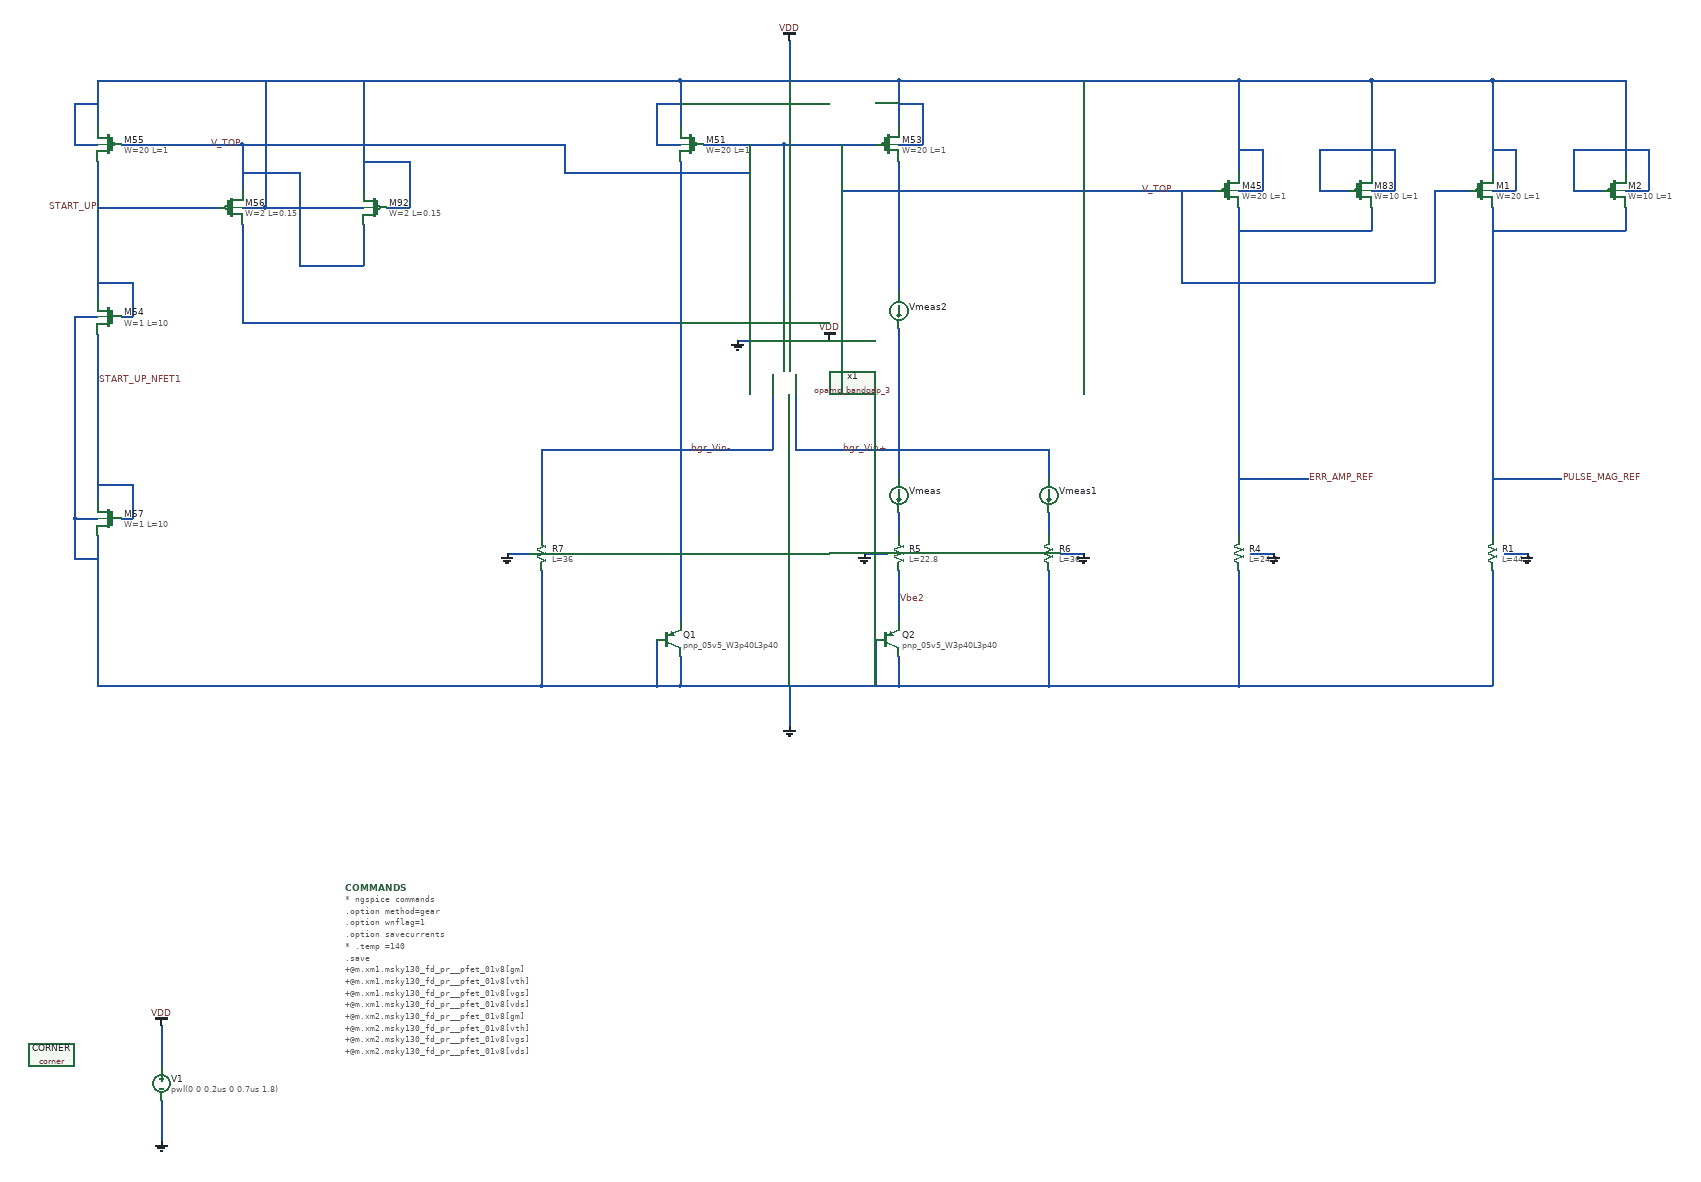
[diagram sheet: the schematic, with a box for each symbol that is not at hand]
v {xschem version=3.4.6 file_version=1.2}
G {}
K {}
V {}
S {}
E {}
B 2 1440 -1170 2430 -300 {flags=graph
y1=-0.0094
y2=1.3
ypos1=0
ypos2=2
divy=5
subdivy=1
unity=1
x1=0
x2=1e-06
divx=5
subdivx=1
xlabmag=1.0
ylabmag=1.0
node=err_amp_ref
color=7
dataset=0
unitx=1
logx=0
logy=0
}
B 2 2630 -1170 3620 -300 {flags=graph
y1=-0.018
y2=1.7
ypos1=0
ypos2=2
divy=5
subdivy=1
unity=1
x1=0
x2=1e-06
divx=5
subdivx=1
xlabmag=1.0
ylabmag=1.0
node=pulse_mag_ref
color=7
dataset=0
unitx=1
logx=0
logy=0
}
B 2 3730 -1170 4720 -300 {flags=graph
y1=-1.4e-13
y2=0.75
ypos1=0
ypos2=2
divy=5
subdivy=1
unity=1
x1=0
x2=1e-06
divx=5
subdivx=1
xlabmag=1.0
ylabmag=1.0


dataset=0
unitx=1
logx=0
logy=0

color=6
node=v_top}
N 2480 -1740 2480 -1540 {lab=GND}
N 2480 -2590 2480 -2430 {
lab=VDD}
N 2480 -2400 2520 -2400 {lab=VDD}
N 2520 -2470 2520 -2400 {lab=VDD}
N 2480 -2470 2520 -2470 {lab=VDD}
N 2480 -2370 2480 -1800 {lab=ERR_AMP_REF}
N 2210 -2470 2210 -2400 {lab=V_TOP}
N 2210 -2590 2210 -2530 {lab=VDD}
N 2300 -2590 2480 -2590 {lab=VDD}
N 1510 -1540 1890 -1540 {
lab=GND}
N 1470 -1620 1470 -1540 {
lab=GND}
N 1850 -1620 1850 -1540 {
lab=GND}
N 1470 -1540 1510 -1540 {
lab=GND}
N 1550 -2480 1690 -2480 {
lab=V_TOP}
N 1690 -2480 1850 -2480 {
lab=V_TOP}
N 1510 -2590 1510 -2510 {
lab=VDD}
N 1510 -2590 1890 -2590 {
lab=VDD}
N 1890 -2590 1890 -2510 {
lab=VDD}
N 1890 -1740 1890 -1650 {lab=Vbe2}
N 2150 -1740 2150 -1540 {lab=GND}
N 1270 -1740 1270 -1540 {lab=GND}
N 1890 -2480 1930 -2480 {lab=VDD}
N 1930 -2550 1930 -2480 {lab=VDD}
N 1890 -2550 1930 -2550 {lab=VDD}
N 1470 -2480 1510 -2480 {lab=VDD}
N 1470 -2550 1470 -2480 {lab=VDD}
N 1470 -2550 1510 -2550 {lab=VDD}
N 1270 -1540 1470 -1540 {lab=GND}
N 1890 -1590 1890 -1540 {lab=GND}
N 1510 -1590 1510 -1540 {lab=GND}
N 750 -2480 750 -2400 {lab=V_TOP}
N 500 -2340 500 -2210 {lab=START_UP}
N 500 -2590 500 -2510 {
lab=VDD}
N 460 -2480 500 -2480 {lab=VDD}
N 460 -2550 460 -2480 {lab=VDD}
N 460 -2550 500 -2550 {lab=VDD}
N 500 -2450 500 -2340 {lab=START_UP}
N 500 -2590 1510 -2590 {lab=VDD}
N 750 -2480 1310 -2480 {lab=V_TOP}
N 1310 -2480 1310 -2430 {lab=V_TOP}
N 1310 -2430 1630 -2430 {lab=V_TOP}
N 500 -2370 710 -2370 {lab=START_UP}
N 500 -1540 1270 -1540 {lab=GND}
N 1630 -2480 1630 -2430 {lab=V_TOP}
N 750 -2170 1510 -2170 {lab=bgr_Vin-}
N 460 -2180 460 -2110 {lab=GND}
N 460 -2180 500 -2180 {lab=GND}
N 500 -1620 500 -1540 {lab=GND}
N 750 -2370 790 -2370 {lab=VDD}
N 500 -1800 500 -1620 {lab=GND}
N 540 -2480 750 -2480 {lab=V_TOP}
N 500 -2240 560 -2240 {lab=START_UP}
N 560 -2240 560 -2180 {lab=START_UP}
N 540 -2180 560 -2180 {lab=START_UP}
N 750 -2340 750 -2170 {lab=bgr_Vin-}
N 1270 -1950 1270 -1800 {lab=bgr_Vin-}
N 1700 -1540 1700 -1470 {lab=GND}
N 1210 -1770 1250 -1770 {lab=GND}
N 1830 -1770 1870 -1770 {lab=GND}
N 2170 -1770 2210 -1770 {lab=GND}
N 1610 -2140 1630 -2140 {lab=GND}
N 1750 -2140 1770 -2140 {lab=VDD}
N 790 -2590 790 -2370 {lab=VDD}
N 1710 -2080 1710 -1950 {lab=bgr_Vin+}
N 1670 -2080 1670 -1950 {lab=bgr_Vin-}
N 1710 -1950 2150 -1950 {lab=bgr_Vin+}
N 1270 -1950 1670 -1950 {lab=bgr_Vin-}
N 1690 -2480 1690 -2210 {lab=V_TOP}
N 1510 -1950 1510 -1650 {lab=bgr_Vin-}
N 1510 -2450 1510 -1950 {lab=bgr_Vin-}
N 460 -1760 500 -1760 {lab=GND}
N 460 -1830 460 -1760 {lab=GND}
N 460 -1830 500 -1830 {lab=GND}
N 500 -1890 560 -1890 {lab=START_UP_NFET1}
N 560 -1890 560 -1830 {lab=START_UP_NFET1}
N 540 -1830 560 -1830 {lab=START_UP_NFET1}
N 500 -2150 500 -1860 {lab=START_UP_NFET1}
N 1890 -1540 2150 -1540 {lab=GND}
N 2150 -1540 2480 -1540 {lab=GND}
N 1890 -2590 2300 -2590 {lab=VDD}
N 1790 -2400 2440 -2400 {lab=V_TOP}
N 1790 -2480 1790 -2400 {lab=V_TOP}
N 2500 -1770 2540 -1770 {lab=GND}
N 1700 -2660 1700 -2590 {lab=VDD}
N 460 -2110 460 -1830 {lab=GND}
N 2710 -2590 2710 -2430 {
lab=VDD}
N 2710 -2400 2750 -2400 {lab=VDD}
N 2750 -2470 2750 -2400 {lab=VDD}
N 2710 -2470 2750 -2470 {lab=VDD}
N 2620 -2400 2670 -2400 {lab=VDD}
N 2620 -2470 2620 -2400 {lab=VDD}
N 2620 -2470 2710 -2470 {lab=VDD}
N 2480 -2330 2710 -2330 {lab=ERR_AMP_REF}
N 2710 -2370 2710 -2330 {lab=ERR_AMP_REF}
N 960 -2340 960 -2270 {lab=V_TOP}
N 790 -2370 960 -2370 {lab=VDD}
N 960 -2590 960 -2400 {lab=VDD}
N 1000 -2370 1040 -2370 {lab=VDD}
N 1040 -2450 1040 -2370 {lab=VDD}
N 960 -2450 1040 -2450 {lab=VDD}
N 750 -2430 850 -2430 {lab=V_TOP}
N 850 -2430 850 -2270 {lab=V_TOP}
N 850 -2270 960 -2270 {lab=V_TOP}
N 2480 -1900 2600 -1900 {lab=ERR_AMP_REF}
N 610 -820 610 -750 {lab=GND}
N 610 -950 610 -880 {lab=VDD}
N 2480 -2590 2710 -2590 {lab=VDD}
N 2920 -1740 2920 -1540 {lab=GND}
N 2920 -2590 2920 -2430 {
lab=VDD}
N 2920 -2400 2960 -2400 {lab=VDD}
N 2960 -2470 2960 -2400 {lab=VDD}
N 2920 -2470 2960 -2470 {lab=VDD}
N 2920 -2370 2920 -1800 {lab=PULSE_MAG_REF}
N 2940 -1770 2980 -1770 {lab=GND}
N 3150 -2590 3150 -2430 {
lab=VDD}
N 3150 -2400 3190 -2400 {lab=VDD}
N 3190 -2470 3190 -2400 {lab=VDD}
N 3150 -2470 3190 -2470 {lab=VDD}
N 3060 -2400 3110 -2400 {lab=VDD}
N 3060 -2470 3060 -2400 {lab=VDD}
N 3060 -2470 3150 -2470 {lab=VDD}
N 2920 -2330 3150 -2330 {lab=PULSE_MAG_REF}
N 3150 -2370 3150 -2330 {lab=PULSE_MAG_REF}
N 2920 -1900 3040 -1900 {lab=PULSE_MAG_REF}
N 2920 -2590 3150 -2590 {lab=VDD}
N 2380 -2400 2380 -2240 {lab=V_TOP}
N 2380 -2240 2820 -2240 {lab=V_TOP}
N 2820 -2400 2820 -2240 {lab=V_TOP}
N 2820 -2400 2880 -2400 {lab=V_TOP}
N 2710 -2590 2920 -2590 {lab=VDD}
N 2480 -1540 2920 -1540 {lab=GND}
N 2150 -1840 2150 -1800 {lab=#net1}
N 2150 -1950 2150 -1900 {lab=bgr_Vin+}
N 1890 -1840 1890 -1800 {lab=#net2}
N 1890 -1950 1890 -1900 {lab=bgr_Vin+}
N 1890 -2160 1890 -1950 {lab=bgr_Vin+}
N 1890 -2450 1890 -2220 {lab=#net3}
C {devices/vsource.sym} 610 -850 0 0 {name=V1 value="pwl(0 0 0.2us 0 0.7us 1.8)" savecurrent=false
* 1.8}
C {devices/gnd.sym} 1700 -1470 0 0 {name=l3 lab=GND}
C {sky130_fd_pr/corner.sym} 420 -900 0 0 {name=CORNER only_toplevel=false corner=tt}
C {simulator_commands_shown.sym} 930 -1190 0 0 {name=COMMANDS
simulator=ngspice
only_toplevel=false 
value="
* ngspice commands


.option method=gear
.option wnflag=1
.option savecurrents
* .temp =140

.save
+@m.xm1.msky130_fd_pr__pfet_01v8[gm]
+@m.xm1.msky130_fd_pr__pfet_01v8[vth]
+@m.xm1.msky130_fd_pr__pfet_01v8[vgs]
+@m.xm1.msky130_fd_pr__pfet_01v8[vds]
+@m.xm2.msky130_fd_pr__pfet_01v8[gm]
+@m.xm2.msky130_fd_pr__pfet_01v8[vth]
+@m.xm2.msky130_fd_pr__pfet_01v8[vgs]
+@m.xm2.msky130_fd_pr__pfet_01v8[vds]
+@m.xm3.msky130_fd_pr__pfet_01v8[gm]
+@m.xm4.msky130_fd_pr__pfet_01v8[gm]
+@m.xm4.msky130_fd_pr__pfet_01v8[vth]
+@m.xm5.msky130_fd_pr__nfet_01v8[gm]
+@m.xm5.msky130_fd_pr__nfet_01v8[vth]
+@m.xm6.msky130_fd_pr__pfet_01v8[gm]
+@m.xm6.msky130_fd_pr__pfet_01v8[vth]
+@m.xm7.msky130_fd_pr__nfet_01v8[gm]
+@m.xm7.msky130_fd_pr__nfet_01v8[vth]
+@m.xm8.msky130_fd_pr__nfet_01v8[gm]
+@m.xm8.msky130_fd_pr__nfet_01v8[vth]
+@m.xm9.msky130_fd_pr__nfet_01v8[gm]
+@m.xm9.msky130_fd_pr__nfet_01v8[vth]
+@m.x1.xm1.msky130_fd_pr__nfet_01v8[gm]
+@m.x1.xm2.msky130_fd_pr__nfet_01v8[gm]
+@m.x1.xm3.msky130_fd_pr__nfet_01v8[gm]
+@m.x1.xm4.msky130_fd_pr__nfet_01v8[gm]
+@m.x1.xm5.msky130_fd_pr__pfet_01v8[gm]
+@m.x1.xm6.msky130_fd_pr__nfet_01v8[gm]
+@m.x1.xm7.msky130_fd_pr__pfet_01v8[gm]

* .ic v(vin-) = 0.8
* .ic v(vin+) = 0.8
* .ic v(v_top) = 1.8

.control

    save all
    * dc temp -40 120 5 V1 1.6 2.0 0.05
    * dc V1 1.7 1.9 0.001 temp -40 120 40
    * dc V1 0.0 2.0 0.02 temp -40 120 20
    * dc V1 0 2.0 0.02
    tran 20ps 1us
    * tran 10ns 10us
    remzerovec
    write tb_ref_volt_cur_gen_dummy_2.raw
.endc

"}
C {sky130_fd_pr/pfet_01v8.sym} 2460 -2400 0 0 {name=M45
W=20
L=1
nf=4
mult=1
ad="'int((nf+1)/2) * W/nf * 0.29'" 
pd="'2*int((nf+1)/2) * (W/nf + 0.29)'"
as="'int((nf+2)/2) * W/nf * 0.29'" 
ps="'2*int((nf+2)/2) * (W/nf + 0.29)'"
nrd="'0.29 / W'" nrs="'0.29 / W'"
sa=0 sb=0 sd=0
model=pfet_01v8
spiceprefix=X
}
C {sky130_fd_pr/res_xhigh_po_0p35.sym} 2480 -1770 0 1 {name=R4
L=24.3
model=res_xhigh_po_0p35
spiceprefix=X
mult=1}
C {lab_wire.sym} 2310 -2400 2 0 {name=p56 sig_type=std_logic lab=V_TOP}
C {devices/lab_pin.sym} 1890 -1690 2 0 {name=p67 sig_type=std_logic lab=Vbe2}
C {sky130_fd_pr/pnp_05v5.sym} 1490 -1620 0 0 {name=Q1
model=pnp_05v5_W3p40L3p40
m=1
spiceprefix=X
}
C {sky130_fd_pr/pnp_05v5.sym} 1870 -1620 0 0 {name=Q2
model=pnp_05v5_W3p40L3p40
m=8
spiceprefix=X
}
C {sky130_fd_pr/pfet_01v8.sym} 1530 -2480 0 1 {name=M51
W=20
L=1
nf=4
mult=1
ad="'int((nf+1)/2) * W/nf * 0.29'" 
pd="'2*int((nf+1)/2) * (W/nf + 0.29)'"
as="'int((nf+2)/2) * W/nf * 0.29'" 
ps="'2*int((nf+2)/2) * (W/nf + 0.29)'"
nrd="'0.29 / W'" nrs="'0.29 / W'"
sa=0 sb=0 sd=0
model=pfet_01v8
spiceprefix=X
}
C {sky130_fd_pr/pfet_01v8.sym} 1870 -2480 0 0 {name=M53
W=20
L=1
nf=4
mult=1
ad="'int((nf+1)/2) * W/nf * 0.29'" 
pd="'2*int((nf+1)/2) * (W/nf + 0.29)'"
as="'int((nf+2)/2) * W/nf * 0.29'" 
ps="'2*int((nf+2)/2) * (W/nf + 0.29)'"
nrd="'0.29 / W'" nrs="'0.29 / W'"
sa=0 sb=0 sd=0
model=pfet_01v8
spiceprefix=X
}
C {lab_wire.sym} 1790 -1950 2 0 {name=p70 sig_type=std_logic lab=bgr_Vin+}
C {lab_wire.sym} 1600 -1950 2 1 {name=p71 sig_type=std_logic lab=bgr_Vin-}
C {sky130_fd_pr/res_xhigh_po_0p35.sym} 2150 -1770 0 1 {name=R6
L=36
model=res_xhigh_po_0p35
spiceprefix=X
mult=1}
C {sky130_fd_pr/res_xhigh_po_0p35.sym} 1270 -1770 0 0 {name=R7
L=36
model=res_xhigh_po_0p35
spiceprefix=X
mult=1}
C {sky130_fd_pr/nfet_01v8.sym} 520 -2180 0 1 {name=M54
W=1
L=10
nf=1 
mult=1
ad="'int((nf+1)/2) * W/nf * 0.29'" 
pd="'2*int((nf+1)/2) * (W/nf + 0.29)'"
as="'int((nf+2)/2) * W/nf * 0.29'" 
ps="'2*int((nf+2)/2) * (W/nf + 0.29)'"
nrd="'0.29 / W'" nrs="'0.29 / W'"
sa=0 sb=0 sd=0
model=nfet_01v8
spiceprefix=X
}
C {sky130_fd_pr/pfet_01v8.sym} 520 -2480 0 1 {name=M55
W=20
L=1
nf=4
mult=1
ad="'int((nf+1)/2) * W/nf * 0.29'" 
pd="'2*int((nf+1)/2) * (W/nf + 0.29)'"
as="'int((nf+2)/2) * W/nf * 0.29'" 
ps="'2*int((nf+2)/2) * (W/nf + 0.29)'"
nrd="'0.29 / W'" nrs="'0.29 / W'"
sa=0 sb=0 sd=0
model=pfet_01v8
spiceprefix=X
}
C {devices/lab_pin.sym} 500 -2370 2 1 {name=p72 sig_type=std_logic lab=START_UP}
C {lab_wire.sym} 750 -2480 0 0 {name=p73 sig_type=std_logic lab=V_TOP}
C {sky130_fd_pr/pfet_01v8.sym} 730 -2370 0 0 {name=M56
W=2
L=0.15
nf=2
mult=1
ad="'int((nf+1)/2) * W/nf * 0.29'" 
pd="'2*int((nf+1)/2) * (W/nf + 0.29)'"
as="'int((nf+2)/2) * W/nf * 0.29'" 
ps="'2*int((nf+2)/2) * (W/nf + 0.29)'"
nrd="'0.29 / W'" nrs="'0.29 / W'"
sa=0 sb=0 sd=0
model=pfet_01v8
spiceprefix=X
}
C {sky130_fd_pr/nfet_01v8.sym} 520 -1830 0 1 {name=M57
W=1
L=10
nf=1 
mult=1
ad="'int((nf+1)/2) * W/nf * 0.29'" 
pd="'2*int((nf+1)/2) * (W/nf + 0.29)'"
as="'int((nf+2)/2) * W/nf * 0.29'" 
ps="'2*int((nf+2)/2) * (W/nf + 0.29)'"
nrd="'0.29 / W'" nrs="'0.29 / W'"
sa=0 sb=0 sd=0
model=nfet_01v8
spiceprefix=X
}
C {devices/lab_pin.sym} 500 -2070 2 0 {name=p90 sig_type=std_logic lab=START_UP_NFET1}
C {sky130_fd_pr/pfet_01v8.sym} 2690 -2400 0 0 {name=M83
W=10
L=1
nf=2
mult=1
ad="'int((nf+1)/2) * W/nf * 0.29'" 
pd="'2*int((nf+1)/2) * (W/nf + 0.29)'"
as="'int((nf+2)/2) * W/nf * 0.29'" 
ps="'2*int((nf+2)/2) * (W/nf + 0.29)'"
nrd="'0.29 / W'" nrs="'0.29 / W'"
sa=0 sb=0 sd=0
model=pfet_01v8
spiceprefix=X
}
C {sky130_fd_pr/pfet_01v8.sym} 980 -2370 0 1 {name=M92
W=2
L=0.15
nf=2
mult=1
ad="'int((nf+1)/2) * W/nf * 0.29'" 
pd="'2*int((nf+1)/2) * (W/nf + 0.29)'"
as="'int((nf+2)/2) * W/nf * 0.29'" 
ps="'2*int((nf+2)/2) * (W/nf + 0.29)'"
nrd="'0.29 / W'" nrs="'0.29 / W'"
sa=0 sb=0 sd=0
model=pfet_01v8
spiceprefix=X
}
C {sky130_fd_pr/res_high_po_0p35.sym} 1890 -1770 0 0 {name=R5
L=22.8
model=res_high_po_0p35
spiceprefix=X
mult=1}
C {devices/gnd.sym} 1210 -1770 0 1 {name=l1 lab=GND}
C {devices/gnd.sym} 1830 -1770 0 1 {name=l2 lab=GND}
C {devices/gnd.sym} 2210 -1770 0 0 {name=l5 lab=GND}
C {devices/gnd.sym} 1610 -2140 1 0 {name=l6 lab=GND}
C {devices/vdd.sym} 1770 -2140 1 0 {name=l7 lab=VDD}
C {devices/gnd.sym} 2540 -1770 0 0 {name=l8 lab=GND}
C {devices/vdd.sym} 1700 -2660 0 0 {name=l11 lab=VDD}
C {devices/gnd.sym} 610 -750 0 0 {name=l12 lab=GND}
C {devices/vdd.sym} 610 -950 0 0 {name=l13 lab=VDD}
C {sky130_fd_pr/pfet_01v8.sym} 2900 -2400 0 0 {name=M1
W=20
L=1
nf=4
mult=1
ad="'int((nf+1)/2) * W/nf * 0.29'" 
pd="'2*int((nf+1)/2) * (W/nf + 0.29)'"
as="'int((nf+2)/2) * W/nf * 0.29'" 
ps="'2*int((nf+2)/2) * (W/nf + 0.29)'"
nrd="'0.29 / W'" nrs="'0.29 / W'"
sa=0 sb=0 sd=0
model=pfet_01v8
spiceprefix=X
}
C {sky130_fd_pr/res_xhigh_po_0p35.sym} 2920 -1770 0 1 {name=R1
L=44.7
model=res_xhigh_po_0p35
spiceprefix=X
mult=1}
C {sky130_fd_pr/pfet_01v8.sym} 3130 -2400 0 0 {name=M2
W=10
L=1
nf=2
mult=1
ad="'int((nf+1)/2) * W/nf * 0.29'" 
pd="'2*int((nf+1)/2) * (W/nf + 0.29)'"
as="'int((nf+2)/2) * W/nf * 0.29'" 
ps="'2*int((nf+2)/2) * (W/nf + 0.29)'"
nrd="'0.29 / W'" nrs="'0.29 / W'"
sa=0 sb=0 sd=0
model=pfet_01v8
spiceprefix=X
}
C {devices/gnd.sym} 2980 -1770 0 0 {name=l4 lab=GND}
C {lab_pin.sym} 2600 -1900 0 1 {name=p61 lab=ERR_AMP_REF}
C {lab_pin.sym} 3040 -1900 0 1 {name=p16 lab=PULSE_MAG_REF}
C {ammeter.sym} 1890 -1870 0 0 {name=Vmeas savecurrent=true spice_ignore=0}
C {ammeter.sym} 2150 -1870 0 0 {name=Vmeas1 savecurrent=true spice_ignore=0}
C {ammeter.sym} 1890 -2190 0 0 {name=Vmeas2 savecurrent=true spice_ignore=0}
C {opamp_bandgap_3.sym} 1690 -2140 1 1 {name=x1}
